VERSION 5.7 ;
  NOWIREEXTENSIONATPIN ON ;
  DIVIDERCHAR "/" ;
  BUSBITCHARS "[]" ;
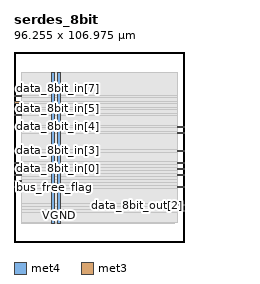
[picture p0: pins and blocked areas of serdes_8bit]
MACRO serdes_8bit
  CLASS BLOCK ;
  FOREIGN serdes_8bit ;
  ORIGIN 0.000 0.000 ;
  SIZE 96.255 BY 106.975 ;
  PIN VGND
    DIRECTION INOUT ;
    USE GROUND ;
    PORT
      LAYER met4 ;
        RECT 24.340 10.640 25.940 95.440 ;
    END
  END VGND
  PIN VPWR
    DIRECTION INOUT ;
    USE POWER ;
    PORT
      LAYER met4 ;
        RECT 21.040 10.640 22.640 95.440 ;
    END
  END VPWR
  PIN bus_free_flag
    DIRECTION OUTPUT ;
    USE SIGNAL ;
    ANTENNADIFFAREA 0.445500 ;
    PORT
      LAYER met3 ;
        RECT 0.000 30.640 4.000 31.240 ;
    END
  END bus_free_flag
  PIN clk
    DIRECTION INPUT ;
    USE SIGNAL ;
    ANTENNAGATEAREA 0.852000 ;
    PORT
      LAYER met3 ;
        RECT 92.255 17.040 96.255 17.640 ;
    END
  END clk
  PIN data_8bit_in[0]
    DIRECTION INPUT ;
    USE SIGNAL ;
    ANTENNAGATEAREA 0.196500 ;
    PORT
      LAYER met3 ;
        RECT 0.000 40.840 4.000 41.440 ;
    END
  END data_8bit_in[0]
  PIN data_8bit_in[1]
    DIRECTION INPUT ;
    USE SIGNAL ;
    ANTENNAGATEAREA 0.196500 ;
    PORT
      LAYER met3 ;
        RECT 0.000 44.240 4.000 44.840 ;
    END
  END data_8bit_in[1]
  PIN data_8bit_in[2]
    DIRECTION INPUT ;
    USE SIGNAL ;
    ANTENNAGATEAREA 0.196500 ;
    PORT
      LAYER met3 ;
        RECT 0.000 37.440 4.000 38.040 ;
    END
  END data_8bit_in[2]
  PIN data_8bit_in[3]
    DIRECTION INPUT ;
    USE SIGNAL ;
    ANTENNAGATEAREA 0.196500 ;
    PORT
      LAYER met3 ;
        RECT 0.000 51.040 4.000 51.640 ;
    END
  END data_8bit_in[3]
  PIN data_8bit_in[4]
    DIRECTION INPUT ;
    USE SIGNAL ;
    ANTENNAGATEAREA 0.196500 ;
    PORT
      LAYER met3 ;
        RECT 0.000 64.640 4.000 65.240 ;
    END
  END data_8bit_in[4]
  PIN data_8bit_in[5]
    DIRECTION INPUT ;
    USE SIGNAL ;
    ANTENNAGATEAREA 0.196500 ;
    PORT
      LAYER met3 ;
        RECT 0.000 74.840 4.000 75.440 ;
    END
  END data_8bit_in[5]
  PIN data_8bit_in[6]
    DIRECTION INPUT ;
    USE SIGNAL ;
    ANTENNAGATEAREA 0.196500 ;
    PORT
      LAYER met3 ;
        RECT 0.000 78.240 4.000 78.840 ;
    END
  END data_8bit_in[6]
  PIN data_8bit_in[7]
    DIRECTION INPUT ;
    USE SIGNAL ;
    ANTENNAGATEAREA 0.196500 ;
    PORT
      LAYER met3 ;
        RECT 0.000 81.640 4.000 82.240 ;
    END
  END data_8bit_in[7]
  PIN data_8bit_out[0]
    DIRECTION OUTPUT ;
    USE SIGNAL ;
    ANTENNADIFFAREA 0.445500 ;
    PORT
      LAYER met3 ;
        RECT 92.255 40.840 96.255 41.440 ;
    END
  END data_8bit_out[0]
  PIN data_8bit_out[1]
    DIRECTION OUTPUT ;
    USE SIGNAL ;
    ANTENNADIFFAREA 0.445500 ;
    PORT
      LAYER met3 ;
        RECT 92.255 44.240 96.255 44.840 ;
    END
  END data_8bit_out[1]
  PIN data_8bit_out[2]
    DIRECTION OUTPUT ;
    USE SIGNAL ;
    ANTENNADIFFAREA 0.445500 ;
    PORT
      LAYER met3 ;
        RECT 92.255 20.440 96.255 21.040 ;
    END
  END data_8bit_out[2]
  PIN data_8bit_out[3]
    DIRECTION OUTPUT ;
    USE SIGNAL ;
    ANTENNADIFFAREA 0.445500 ;
    PORT
      LAYER met3 ;
        RECT 92.255 30.640 96.255 31.240 ;
    END
  END data_8bit_out[3]
  PIN data_8bit_out[4]
    DIRECTION OUTPUT ;
    USE SIGNAL ;
    ANTENNADIFFAREA 0.445500 ;
    PORT
      LAYER met3 ;
        RECT 92.255 37.440 96.255 38.040 ;
    END
  END data_8bit_out[4]
  PIN data_8bit_out[5]
    DIRECTION OUTPUT ;
    USE SIGNAL ;
    ANTENNADIFFAREA 0.445500 ;
    PORT
      LAYER met3 ;
        RECT 92.255 51.040 96.255 51.640 ;
    END
  END data_8bit_out[5]
  PIN data_8bit_out[6]
    DIRECTION OUTPUT ;
    USE SIGNAL ;
    ANTENNADIFFAREA 0.445500 ;
    PORT
      LAYER met3 ;
        RECT 92.255 64.640 96.255 65.240 ;
    END
  END data_8bit_out[6]
  PIN data_8bit_out[7]
    DIRECTION OUTPUT ;
    USE SIGNAL ;
    ANTENNADIFFAREA 0.445500 ;
    PORT
      LAYER met3 ;
        RECT 92.255 61.240 96.255 61.840 ;
    END
  END data_8bit_out[7]
  PIN data_en
    DIRECTION INPUT ;
    USE SIGNAL ;
    ANTENNAGATEAREA 0.196500 ;
    PORT
      LAYER met3 ;
        RECT 0.000 34.040 4.000 34.640 ;
    END
  END data_en
  PIN rst_n
    DIRECTION INPUT ;
    USE SIGNAL ;
    ANTENNAGATEAREA 0.196500 ;
    PORT
      LAYER met3 ;
        RECT 0.000 71.440 4.000 72.040 ;
    END
  END rst_n
  OBS
      LAYER nwell ;
        RECT 5.330 10.795 90.810 95.390 ;
      LAYER li1 ;
        RECT 5.520 10.795 90.620 95.285 ;
      LAYER met1 ;
        RECT 4.210 10.640 90.620 95.440 ;
      LAYER met2 ;
        RECT 4.230 10.695 89.140 95.385 ;
      LAYER met3 ;
        RECT 3.990 82.640 92.255 95.365 ;
        RECT 4.400 81.240 92.255 82.640 ;
        RECT 3.990 79.240 92.255 81.240 ;
        RECT 4.400 77.840 92.255 79.240 ;
        RECT 3.990 75.840 92.255 77.840 ;
        RECT 4.400 74.440 92.255 75.840 ;
        RECT 3.990 72.440 92.255 74.440 ;
        RECT 4.400 71.040 92.255 72.440 ;
        RECT 3.990 65.640 92.255 71.040 ;
        RECT 4.400 64.240 91.855 65.640 ;
        RECT 3.990 62.240 92.255 64.240 ;
        RECT 3.990 60.840 91.855 62.240 ;
        RECT 3.990 52.040 92.255 60.840 ;
        RECT 4.400 50.640 91.855 52.040 ;
        RECT 3.990 45.240 92.255 50.640 ;
        RECT 4.400 43.840 91.855 45.240 ;
        RECT 3.990 41.840 92.255 43.840 ;
        RECT 4.400 40.440 91.855 41.840 ;
        RECT 3.990 38.440 92.255 40.440 ;
        RECT 4.400 37.040 91.855 38.440 ;
        RECT 3.990 35.040 92.255 37.040 ;
        RECT 4.400 33.640 92.255 35.040 ;
        RECT 3.990 31.640 92.255 33.640 ;
        RECT 4.400 30.240 91.855 31.640 ;
        RECT 3.990 21.440 92.255 30.240 ;
        RECT 3.990 20.040 91.855 21.440 ;
        RECT 3.990 18.040 92.255 20.040 ;
        RECT 3.990 16.640 91.855 18.040 ;
        RECT 3.990 10.715 92.255 16.640 ;
  END
END serdes_8bit
END LIBRARY

